VERSION 5.8 ;
BUSBITCHARS "[]" ;
DIVIDERCHAR "/" ;

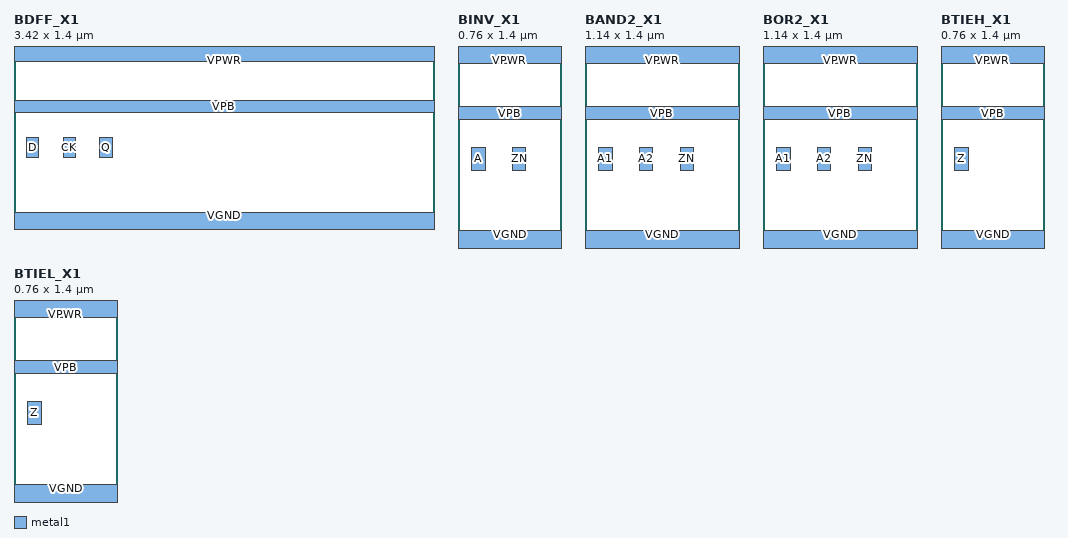
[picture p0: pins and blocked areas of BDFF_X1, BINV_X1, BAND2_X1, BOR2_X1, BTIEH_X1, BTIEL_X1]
MACRO BDFF_X1
  CLASS CORE ; ORIGIN 0 0 ; FOREIGN BDFF_X1 0 0 ; SIZE 3.42 BY 1.4 ; SYMMETRY X Y ; SITE FreePDK45_38x28_10R_NP_162NW_34O ;
  PIN D DIRECTION INPUT ; USE SIGNAL ; PORT LAYER metal1 ; RECT 0.10 0.53 0.20 0.7 ; END END D
  PIN CK DIRECTION INPUT ; USE SIGNAL ; PORT LAYER metal1 ; RECT 0.40 0.53 0.50 0.7 ; END END CK
  PIN Q DIRECTION OUTPUT ; USE SIGNAL ; PORT LAYER metal1 ; RECT 0.70 0.53 0.80 0.7 ; END END Q
  PIN VPWR DIRECTION INOUT ; USE POWER ; SHAPE ABUTMENT ; PORT LAYER metal1 ; RECT 0 1.315 3.42 1.485 ; END END VPWR
  PIN VPB DIRECTION INOUT ; USE POWER ; SHAPE ABUTMENT ; PORT LAYER metal1 ; RECT 0 0.900 3.42 1.000 ; END END VPB
  PIN VGND DIRECTION INOUT ; USE GROUND ; SHAPE ABUTMENT ; PORT LAYER metal1 ; RECT 0 -0.085 3.42 0.085 ; END END VGND
END BDFF_X1

MACRO BINV_X1
  CLASS CORE ; ORIGIN 0 0 ; FOREIGN BINV_X1 0 0 ; SIZE 0.76 BY 1.4 ; SYMMETRY X Y ; SITE FreePDK45_38x28_10R_NP_162NW_34O ;
  PIN A DIRECTION INPUT ; USE SIGNAL ; PORT LAYER metal1 ; RECT 0.10 0.53 0.20 0.7 ; END END A
  PIN ZN DIRECTION OUTPUT ; USE SIGNAL ; PORT LAYER metal1 ; RECT 0.40 0.53 0.50 0.7 ; END END ZN
  PIN VPWR DIRECTION INOUT ; USE POWER ; SHAPE ABUTMENT ; PORT LAYER metal1 ; RECT 0 1.315 0.76 1.485 ; END END VPWR
  PIN VPB DIRECTION INOUT ; USE POWER ; SHAPE ABUTMENT ; PORT LAYER metal1 ; RECT 0 0.900 0.76 1.000 ; END END VPB
  PIN VGND DIRECTION INOUT ; USE GROUND ; SHAPE ABUTMENT ; PORT LAYER metal1 ; RECT 0 -0.085 0.76 0.085 ; END END VGND
END BINV_X1

MACRO BAND2_X1
  CLASS CORE ; ORIGIN 0 0 ; FOREIGN BAND2_X1 0 0 ; SIZE 1.14 BY 1.4 ; SYMMETRY X Y ; SITE FreePDK45_38x28_10R_NP_162NW_34O ;
  PIN A1 DIRECTION INPUT ; USE SIGNAL ; PORT LAYER metal1 ; RECT 0.10 0.53 0.20 0.7 ; END END A1
  PIN A2 DIRECTION INPUT ; USE SIGNAL ; PORT LAYER metal1 ; RECT 0.40 0.53 0.50 0.7 ; END END A2
  PIN ZN DIRECTION OUTPUT ; USE SIGNAL ; PORT LAYER metal1 ; RECT 0.70 0.53 0.80 0.7 ; END END ZN
  PIN VPWR DIRECTION INOUT ; USE POWER ; SHAPE ABUTMENT ; PORT LAYER metal1 ; RECT 0 1.315 1.14 1.485 ; END END VPWR
  PIN VPB DIRECTION INOUT ; USE POWER ; SHAPE ABUTMENT ; PORT LAYER metal1 ; RECT 0 0.900 1.14 1.000 ; END END VPB
  PIN VGND DIRECTION INOUT ; USE GROUND ; SHAPE ABUTMENT ; PORT LAYER metal1 ; RECT 0 -0.085 1.14 0.085 ; END END VGND
END BAND2_X1

MACRO BOR2_X1
  CLASS CORE ; ORIGIN 0 0 ; FOREIGN BOR2_X1 0 0 ; SIZE 1.14 BY 1.4 ; SYMMETRY X Y ; SITE FreePDK45_38x28_10R_NP_162NW_34O ;
  PIN A1 DIRECTION INPUT ; USE SIGNAL ; PORT LAYER metal1 ; RECT 0.10 0.53 0.20 0.7 ; END END A1
  PIN A2 DIRECTION INPUT ; USE SIGNAL ; PORT LAYER metal1 ; RECT 0.40 0.53 0.50 0.7 ; END END A2
  PIN ZN DIRECTION OUTPUT ; USE SIGNAL ; PORT LAYER metal1 ; RECT 0.70 0.53 0.80 0.7 ; END END ZN
  PIN VPWR DIRECTION INOUT ; USE POWER ; SHAPE ABUTMENT ; PORT LAYER metal1 ; RECT 0 1.315 1.14 1.485 ; END END VPWR
  PIN VPB DIRECTION INOUT ; USE POWER ; SHAPE ABUTMENT ; PORT LAYER metal1 ; RECT 0 0.900 1.14 1.000 ; END END VPB
  PIN VGND DIRECTION INOUT ; USE GROUND ; SHAPE ABUTMENT ; PORT LAYER metal1 ; RECT 0 -0.085 1.14 0.085 ; END END VGND
END BOR2_X1

MACRO BTIEH_X1
  CLASS CORE ; ORIGIN 0 0 ; FOREIGN BTIEH_X1 0 0 ; SIZE 0.76 BY 1.4 ; SYMMETRY X Y ; SITE FreePDK45_38x28_10R_NP_162NW_34O ;
  PIN Z DIRECTION OUTPUT ; USE SIGNAL ; PORT LAYER metal1 ; RECT 0.10 0.53 0.20 0.7 ; END END Z
  PIN VPWR DIRECTION INOUT ; USE POWER ; SHAPE ABUTMENT ; PORT LAYER metal1 ; RECT 0 1.315 0.76 1.485 ; END END VPWR
  PIN VPB DIRECTION INOUT ; USE POWER ; SHAPE ABUTMENT ; PORT LAYER metal1 ; RECT 0 0.900 0.76 1.000 ; END END VPB
  PIN VGND DIRECTION INOUT ; USE GROUND ; SHAPE ABUTMENT ; PORT LAYER metal1 ; RECT 0 -0.085 0.76 0.085 ; END END VGND
END BTIEH_X1

MACRO BTIEL_X1
  CLASS CORE ; ORIGIN 0 0 ; FOREIGN BTIEL_X1 0 0 ; SIZE 0.76 BY 1.4 ; SYMMETRY X Y ; SITE FreePDK45_38x28_10R_NP_162NW_34O ;
  PIN Z DIRECTION OUTPUT ; USE SIGNAL ; PORT LAYER metal1 ; RECT 0.10 0.53 0.20 0.7 ; END END Z
  PIN VPWR DIRECTION INOUT ; USE POWER ; SHAPE ABUTMENT ; PORT LAYER metal1 ; RECT 0 1.315 0.76 1.485 ; END END VPWR
  PIN VPB DIRECTION INOUT ; USE POWER ; SHAPE ABUTMENT ; PORT LAYER metal1 ; RECT 0 0.900 0.76 1.000 ; END END VPB
  PIN VGND DIRECTION INOUT ; USE GROUND ; SHAPE ABUTMENT ; PORT LAYER metal1 ; RECT 0 -0.085 0.76 0.085 ; END END VGND
END BTIEL_X1

END LIBRARY
